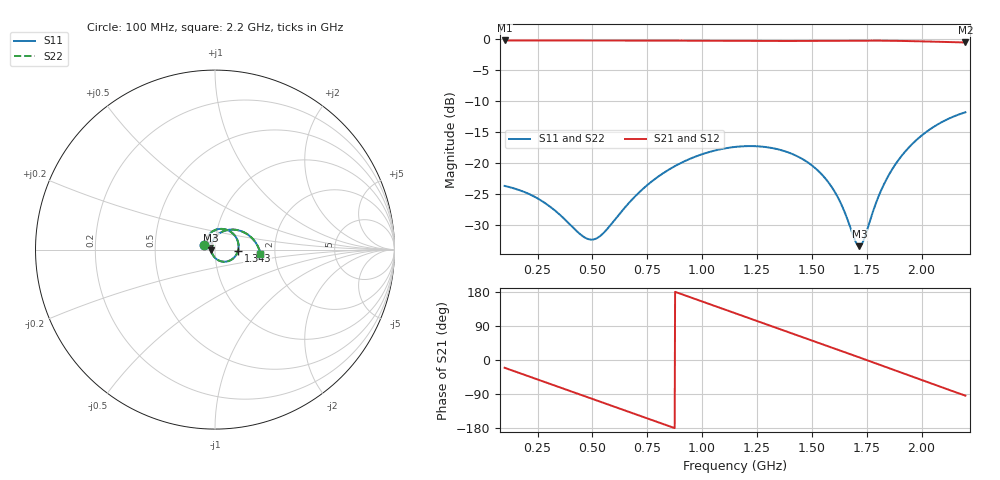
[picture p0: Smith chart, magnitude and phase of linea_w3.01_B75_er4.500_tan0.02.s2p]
! Chirptenna · simulación 3D de una microstrip de dos puertos (S12 = S21, S22 = S11 por simetría)
# HZ S RI R 50
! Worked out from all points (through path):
!   1101 points, 100 MHz to 2.2 GHz, reference 50 ohm
!   highest |S21| = -0.31 dB at 100 MHz (marker M1); lowest = -0.6 dB at 2.2 GHz (marker M2)
!   group delay of S21, straight-line fit = 573 ps
!   lowest |S11| = -33.5 dB at 1.717 GHz (marker M3), VSWR 1.04, Z = 47.9 - j0.293 ohm
!   |S11| at or under -10 dB: start of sweep to end of sweep
!   |S22| runs from -33.5 to -11.9 dB; largest |S21 - S12| = 0
!   S11 on the Smith chart (normalised r, x): 100 MHz: 0.89, +0.04; 1.343 GHz: 1.29, -0.02; 2.2 GHz: 1.68, -0.08
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1e8  -0.0602 0.0238  0.9033 -0.3378  0.9033 -0.3378  -0.0602 0.0238
1.878182e8  -0.0446 0.0371  0.7546 -0.6005  0.7546 -0.6005  -0.0446 0.0371
2.89e8  -0.0248 0.0393  0.4928 -0.8289  0.4928 -0.8289  -0.0248 0.0393
3.710909e8  -0.0141 0.0323  0.2314 -0.9361  0.2314 -0.9361  -0.0141 0.0323
4.512727e8  -0.0123 0.0227  -0.0434 -0.9632  -0.0434 -0.9632  -0.0123 0.0227
5.2e8  -0.0177 0.017  -0.277 -0.9233  -0.277 -0.9233  -0.0177 0.017
6.116364e8  -0.0309 0.0188  -0.5601 -0.7839  -0.5601 -0.7839  -0.0309 0.0188
7.09e8  -0.0433 0.0363  -0.7941 -0.5441  -0.7941 -0.5441  -0.0433 0.0363
8.006364e8  -0.0426 0.0642  -0.9262 -0.2579  -0.9262 -0.2579  -0.0426 0.0642
8.846364e8  -0.0258 0.0917  -0.9595 0.0289  -0.9595 0.0289  -0.0258 0.0917
9.686364e8  0.00656 0.1112  -0.9061 0.3118  -0.9061 0.3118  0.00656 0.1112
1.15e9  0.0966 0.0923  -0.5313 0.7933  -0.5313 0.7933  0.0966 0.0923
1.247364e9  0.127 0.0467  -0.2289 0.9261  -0.2289 0.9261  0.127 0.0467
1.342818e9  0.128 -0.00711  0.0944 0.9497  0.0944 0.9497  0.128 -0.00711
1.501273e9  0.0679 -0.0657  0.5936 0.7516  0.5936 0.7516  0.0679 -0.0657
1.604364e9  0.0135 -0.0565  0.8294 0.4844  0.8294 0.4844  0.0135 -0.0565
1.717e9  -0.0209 -0.00306  0.9556 0.1122  0.9556 0.1122  -0.0209 -0.00306
1.850636e9  0.00915 0.0786  0.8928 -0.3509  0.8928 -0.3509  0.00915 0.0786
1.930818e9  0.0641 0.108  0.7486 -0.5921  0.7486 -0.5921  0.0641 0.108
2.032e9  0.1514 0.1006  0.4798 -0.8147  0.4798 -0.8147  0.1514 0.1006
2.116e9  0.2158 0.0533  0.2126 -0.9125  0.2126 -0.9125  0.2158 0.0533
2.2e9  0.2531 -0.0222  -0.066 -0.9267  -0.066 -0.9267  0.2531 -0.0222
